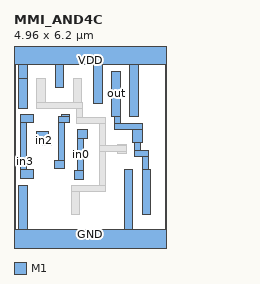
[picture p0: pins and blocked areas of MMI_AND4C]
MACRO MMI_AND4C
	CLASS CORE ;
	FOREIGN MMI_AND4C 0 0 ;
	SIZE 4.96 BY 6.2 ;
	SYMMETRY X Y ;
	SITE CORE1 ;
	PIN out
		DIRECTION output ;
		USE SIGNAL ;
		PORT
			LAYER M1 ;
			RECT 3.195 4.11 3.475 5.58 ;
			LAYER M1 ;
			RECT 3.275 3.875 3.465 4.11 ;
			LAYER M1 ;
			RECT 3.275 3.68 4.19 3.875 ;
			LAYER M1 ;
			RECT 3.865 3.255 4.19 3.68 ;
			LAYER M1 ;
			RECT 3.935 2.985 4.125 3.255 ;
			LAYER M1 ;
			RECT 3.935 2.79 4.385 2.985 ;
			LAYER M1 ;
			RECT 4.19 2.355 4.385 2.79 ;
			LAYER M1 ;
			RECT 4.19 0.885 4.47 2.355 ;
		END
		AntennaDiffArea 1.2859 ;
	END out
	PIN in1
		DIRECTION input ;
		USE SIGNAL ;
		PORT
			LAYER M1 ;
			RECT 1.535 4.08 1.815 4.165 ;
			LAYER M1 ;
			RECT 1.455 3.885 1.815 4.08 ;
			LAYER M1 ;
			RECT 1.455 2.675 1.645 3.885 ;
			LAYER M1 ;
			RECT 1.33 2.395 1.645 2.675 ;
		END
		AntennaGateArea 0.468 ;
	END in1
	PIN GND
		DIRECTION inout ;
		USE GROUND ;
		PORT
			LAYER M1 ;
			RECT 0.16 0.42 0.44 1.855 ;
			LAYER M1 ;
			RECT 3.6 0.42 3.88 2.355 ;
			LAYER M1 ;
			RECT 0 -0.42 4.96 0.42 ;
		END
	END GND
	PIN in2
		DIRECTION input ;
		USE SIGNAL ;
		PORT
			LAYER M1 ;
			RECT 0.74 3.43 1.12 3.6 ;
			LAYER M1 ;
			RECT 0.74 3.22 1.21 3.43 ;
			LAYER M1 ;
			RECT 0.93 3.15 1.21 3.22 ;
		END
		AntennaGateArea 0.468 ;
	END in2
	PIN VDD
		DIRECTION inout ;
		USE POWER ;
		PORT
			LAYER M1 ;
			RECT 0 5.78 4.96 6.62 ;
			LAYER M1 ;
			RECT 0.15 5.335 0.43 5.78 ;
			LAYER M1 ;
			RECT 0.16 4.365 0.44 5.335 ;
			LAYER M1 ;
			RECT 1.34 5.055 1.62 5.78 ;
			LAYER M1 ;
			RECT 2.605 4.52 2.885 5.78 ;
			LAYER M1 ;
			RECT 3.785 4.11 4.065 5.78 ;
		END
	END VDD
	PIN in3
		DIRECTION input ;
		USE SIGNAL ;
		PORT
			LAYER M1 ;
			RECT 0.215 3.885 0.635 4.165 ;
			LAYER M1 ;
			RECT 0.215 2.355 0.405 3.885 ;
			LAYER M1 ;
			RECT 0.215 2.075 0.635 2.355 ;
		END
		AntennaGateArea 0.468 ;
	END in3
	PIN in0
		DIRECTION input ;
		USE SIGNAL ;
		PORT
			LAYER M1 ;
			RECT 2.075 3.375 2.405 3.655 ;
			LAYER M1 ;
			RECT 2.075 2.335 2.265 3.375 ;
			LAYER M1 ;
			RECT 1.985 2.055 2.265 2.335 ;
		END
		AntennaGateArea 0.468 ;
	END in0
	OBS
		LAYER M1 ;
		RECT 0.75 4.56 1.03 5.335 ;
		LAYER M1 ;
		RECT 1.93 4.56 2.21 5.335 ;
		LAYER M1 ;
		RECT 0.75 4.365 2.245 4.56 ;
		LAYER M1 ;
		RECT 2.055 4.06 2.245 4.365 ;
		LAYER M1 ;
		RECT 2.055 3.865 2.99 4.06 ;
		LAYER M1 ;
		RECT 2.8 3.14 2.99 3.865 ;
		LAYER M1 ;
		RECT 3.385 3.14 3.665 3.18 ;
		LAYER M1 ;
		RECT 2.8 2.945 3.665 3.14 ;
		LAYER M1 ;
		RECT 2.8 1.855 2.99 2.945 ;
		LAYER M1 ;
		RECT 3.385 2.9 3.665 2.945 ;
		LAYER M1 ;
		RECT 1.86 1.66 2.99 1.855 ;
		LAYER M1 ;
		RECT 1.86 0.885 2.14 1.66 ;
	END
END MMI_AND4C
